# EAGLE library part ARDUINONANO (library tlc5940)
Arduino nano atmega328 con los pineados de sparkfun

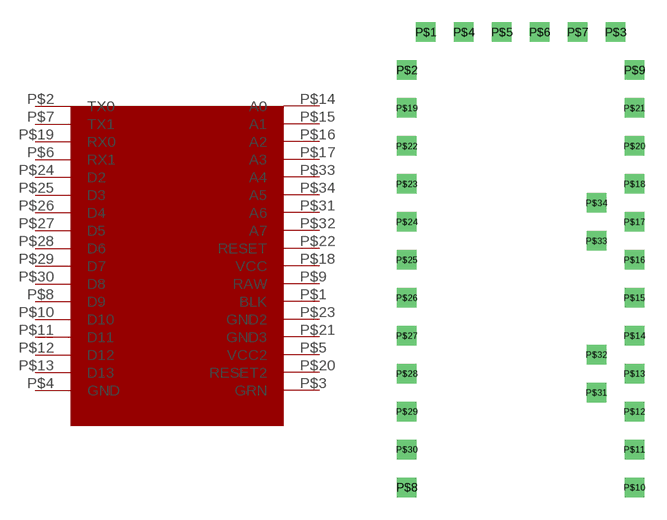
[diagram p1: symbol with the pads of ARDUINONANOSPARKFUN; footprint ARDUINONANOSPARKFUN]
Designator prefix -

## ARDUINONANO  [ARDUINONANOSPARKFUN]
P$1  BLK
P$2  TX0
P$3  GRN
P$4  GND
P$5  VCC2
P$6  RX1
P$7  TX1
P$8  D9
P$9  RAW
P$10  D10
P$11  D11
P$12  D12
P$13  D13
P$14  A0
P$15  A1
P$16  A2
P$17  A3
P$18  VCC
P$19  RX0
P$20  RESET2
P$21  GND3
P$22  RESET
P$23  GND2
P$24  D2
P$25  D3
P$26  D4
P$27  D5
P$28  D6
P$29  D7
P$30  D8
P$31  A6
P$32  A7
P$33  A4
P$34  A5

## Footprint ARDUINONANOSPARKFUN (pad centres in mm)
drill 0.8 square: P$1 -6.35,17.78; P$2 -7.62,15.24; P$3 6.35,17.78; P$4 -3.81,17.78; P$5 -1.27,17.78; P$6 1.27,17.78; P$7 3.81,17.78; P$8 -7.62,-12.7; P$9 7.62,15.24; P$10 7.62,-12.7; P$11 7.62,-10.16; P$12 7.62,-7.62; P$13 7.62,-5.08; P$14 7.62,-2.54; P$15 7.62,0; P$16 7.62,2.54; P$17 7.62,5.08; P$18 7.62,7.62; P$19 -7.62,12.7; P$20 7.62,10.16; P$21 7.62,12.7; P$22 -7.62,10.16; P$23 -7.62,7.62; P$24 -7.62,5.08; P$25 -7.62,2.54; P$26 -7.62,0; P$27 -7.62,-2.54; P$28 -7.62,-5.08; P$29 -7.62,-7.62; P$30 -7.62,-10.16; P$31 5.08,-6.35; P$32 5.08,-3.81; P$33 5.08,3.81; P$34 5.08,6.35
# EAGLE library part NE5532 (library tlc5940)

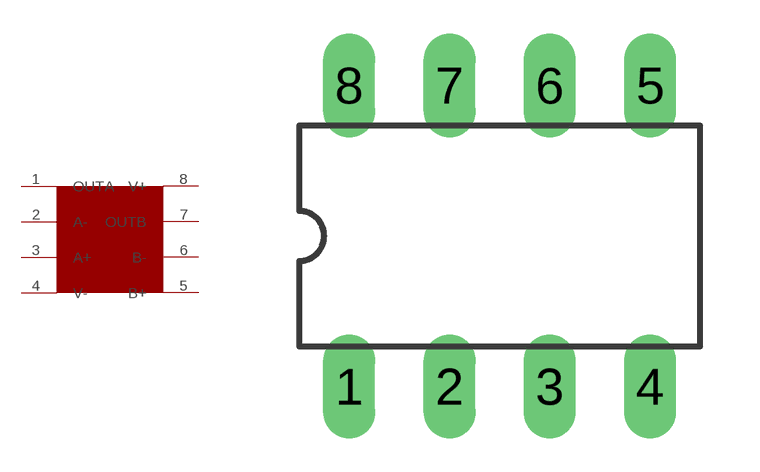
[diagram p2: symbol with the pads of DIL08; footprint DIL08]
Designator prefix -

## NE5532  [DIL08]
1  OUTA
2  A-
3  A+
4  V-
5  B+
6  B-
7  OUTB
8  V+

## Footprint DIL08 (pad centres in mm)
Dual In Line
drill 0.813 long: 1 -3.81,-3.81; 2 -1.27,-3.81; 3 1.27,-3.81; 4 3.81,-3.81; 5 3.81,3.81; 6 1.27,3.81; 7 -1.27,3.81; 8 -3.81,3.81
